VERSION 5.8 ;
BUSBITCHARS "[]" ;
DIVIDERCHAR "/" ;
UNITS
    DATABASE MICRONS 1000 ;
END UNITS

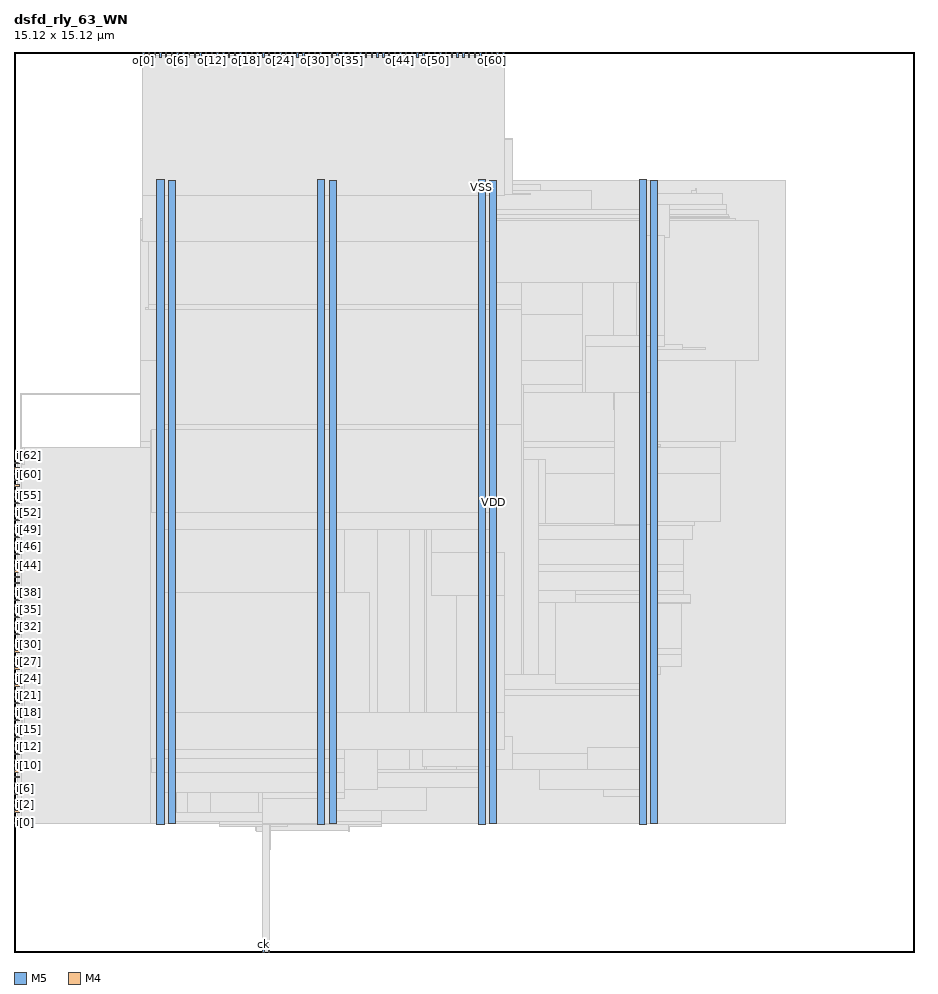
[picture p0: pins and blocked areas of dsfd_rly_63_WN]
MACRO dsfd_rly_63_WN
  FOREIGN dsfd_rly_63_WN 0 0 ;
  CLASS BLOCK ;
  SIZE 15.12 BY 15.12 ;
  PIN ck
    DIRECTION INPUT ;
    USE SIGNAL ;
    PORT
      LAYER M5 ;
        RECT  4.176 0 4.2 0.084 ;
    END
  END ck
  PIN i[0]
    DIRECTION INPUT ;
    USE SIGNAL ;
    PORT
      LAYER M4 ;
        RECT  0 2.16 0.084 2.184 ;
    END
  END i[0]
  PIN i[10]
    DIRECTION INPUT ;
    USE SIGNAL ;
    PORT
      LAYER M4 ;
        RECT  0 3.12 0.084 3.144 ;
    END
  END i[10]
  PIN i[11]
    DIRECTION INPUT ;
    USE SIGNAL ;
    PORT
      LAYER M4 ;
        RECT  0 3.216 0.084 3.24 ;
    END
  END i[11]
  PIN i[12]
    DIRECTION INPUT ;
    USE SIGNAL ;
    PORT
      LAYER M4 ;
        RECT  0 3.312 0.084 3.336 ;
    END
  END i[12]
  PIN i[13]
    DIRECTION INPUT ;
    USE SIGNAL ;
    PORT
      LAYER M4 ;
        RECT  0 3.408 0.084 3.432 ;
    END
  END i[13]
  PIN i[14]
    DIRECTION INPUT ;
    USE SIGNAL ;
    PORT
      LAYER M4 ;
        RECT  0 3.504 0.084 3.528 ;
    END
  END i[14]
  PIN i[15]
    DIRECTION INPUT ;
    USE SIGNAL ;
    PORT
      LAYER M4 ;
        RECT  0 3.6 0.084 3.624 ;
    END
  END i[15]
  PIN i[16]
    DIRECTION INPUT ;
    USE SIGNAL ;
    PORT
      LAYER M4 ;
        RECT  0 3.696 0.084 3.72 ;
    END
  END i[16]
  PIN i[17]
    DIRECTION INPUT ;
    USE SIGNAL ;
    PORT
      LAYER M4 ;
        RECT  0 3.792 0.084 3.816 ;
    END
  END i[17]
  PIN i[18]
    DIRECTION INPUT ;
    USE SIGNAL ;
    PORT
      LAYER M4 ;
        RECT  0 3.888 0.084 3.912 ;
    END
  END i[18]
  PIN i[19]
    DIRECTION INPUT ;
    USE SIGNAL ;
    PORT
      LAYER M4 ;
        RECT  0 3.984 0.084 4.008 ;
    END
  END i[19]
  PIN i[1]
    DIRECTION INPUT ;
    USE SIGNAL ;
    PORT
      LAYER M4 ;
        RECT  0 2.256 0.084 2.28 ;
    END
  END i[1]
  PIN i[20]
    DIRECTION INPUT ;
    USE SIGNAL ;
    PORT
      LAYER M4 ;
        RECT  0 4.08 0.084 4.104 ;
    END
  END i[20]
  PIN i[21]
    DIRECTION INPUT ;
    USE SIGNAL ;
    PORT
      LAYER M4 ;
        RECT  0 4.176 0.084 4.2 ;
    END
  END i[21]
  PIN i[22]
    DIRECTION INPUT ;
    USE SIGNAL ;
    PORT
      LAYER M4 ;
        RECT  0 4.272 0.084 4.296 ;
    END
  END i[22]
  PIN i[23]
    DIRECTION INPUT ;
    USE SIGNAL ;
    PORT
      LAYER M4 ;
        RECT  0 4.368 0.084 4.392 ;
    END
  END i[23]
  PIN i[24]
    DIRECTION INPUT ;
    USE SIGNAL ;
    PORT
      LAYER M4 ;
        RECT  0 4.464 0.084 4.488 ;
    END
  END i[24]
  PIN i[25]
    DIRECTION INPUT ;
    USE SIGNAL ;
    PORT
      LAYER M4 ;
        RECT  0 4.56 0.084 4.584 ;
    END
  END i[25]
  PIN i[26]
    DIRECTION INPUT ;
    USE SIGNAL ;
    PORT
      LAYER M4 ;
        RECT  0 4.656 0.084 4.68 ;
    END
  END i[26]
  PIN i[27]
    DIRECTION INPUT ;
    USE SIGNAL ;
    PORT
      LAYER M4 ;
        RECT  0 4.752 0.084 4.776 ;
    END
  END i[27]
  PIN i[28]
    DIRECTION INPUT ;
    USE SIGNAL ;
    PORT
      LAYER M4 ;
        RECT  0 4.848 0.084 4.872 ;
    END
  END i[28]
  PIN i[29]
    DIRECTION INPUT ;
    USE SIGNAL ;
    PORT
      LAYER M4 ;
        RECT  0 4.944 0.084 4.968 ;
    END
  END i[29]
  PIN i[2]
    DIRECTION INPUT ;
    USE SIGNAL ;
    PORT
      LAYER M4 ;
        RECT  0 2.352 0.084 2.376 ;
    END
  END i[2]
  PIN i[30]
    DIRECTION INPUT ;
    USE SIGNAL ;
    PORT
      LAYER M4 ;
        RECT  0 5.04 0.084 5.064 ;
    END
  END i[30]
  PIN i[31]
    DIRECTION INPUT ;
    USE SIGNAL ;
    PORT
      LAYER M4 ;
        RECT  0 5.136 0.084 5.16 ;
    END
  END i[31]
  PIN i[32]
    DIRECTION INPUT ;
    USE SIGNAL ;
    PORT
      LAYER M4 ;
        RECT  0 5.328 0.084 5.352 ;
    END
  END i[32]
  PIN i[33]
    DIRECTION INPUT ;
    USE SIGNAL ;
    PORT
      LAYER M4 ;
        RECT  0 5.424 0.084 5.448 ;
    END
  END i[33]
  PIN i[34]
    DIRECTION INPUT ;
    USE SIGNAL ;
    PORT
      LAYER M4 ;
        RECT  0 5.52 0.084 5.544 ;
    END
  END i[34]
  PIN i[35]
    DIRECTION INPUT ;
    USE SIGNAL ;
    PORT
      LAYER M4 ;
        RECT  0 5.616 0.084 5.64 ;
    END
  END i[35]
  PIN i[36]
    DIRECTION INPUT ;
    USE SIGNAL ;
    PORT
      LAYER M4 ;
        RECT  0 5.712 0.084 5.736 ;
    END
  END i[36]
  PIN i[37]
    DIRECTION INPUT ;
    USE SIGNAL ;
    PORT
      LAYER M4 ;
        RECT  0 5.808 0.084 5.832 ;
    END
  END i[37]
  PIN i[38]
    DIRECTION INPUT ;
    USE SIGNAL ;
    PORT
      LAYER M4 ;
        RECT  0 5.904 0.084 5.928 ;
    END
  END i[38]
  PIN i[39]
    DIRECTION INPUT ;
    USE SIGNAL ;
    PORT
      LAYER M4 ;
        RECT  0 6 0.084 6.024 ;
    END
  END i[39]
  PIN i[3]
    DIRECTION INPUT ;
    USE SIGNAL ;
    PORT
      LAYER M4 ;
        RECT  0 2.448 0.084 2.472 ;
    END
  END i[3]
  PIN i[40]
    DIRECTION INPUT ;
    USE SIGNAL ;
    PORT
      LAYER M4 ;
        RECT  0 6.096 0.084 6.12 ;
    END
  END i[40]
  PIN i[41]
    DIRECTION INPUT ;
    USE SIGNAL ;
    PORT
      LAYER M4 ;
        RECT  0 6.192 0.084 6.216 ;
    END
  END i[41]
  PIN i[42]
    DIRECTION INPUT ;
    USE SIGNAL ;
    PORT
      LAYER M4 ;
        RECT  0 6.288 0.084 6.312 ;
    END
  END i[42]
  PIN i[43]
    DIRECTION INPUT ;
    USE SIGNAL ;
    PORT
      LAYER M4 ;
        RECT  0 6.384 0.084 6.408 ;
    END
  END i[43]
  PIN i[44]
    DIRECTION INPUT ;
    USE SIGNAL ;
    PORT
      LAYER M4 ;
        RECT  0 6.48 0.084 6.504 ;
    END
  END i[44]
  PIN i[45]
    DIRECTION INPUT ;
    USE SIGNAL ;
    PORT
      LAYER M4 ;
        RECT  0 6.576 0.084 6.6 ;
    END
  END i[45]
  PIN i[46]
    DIRECTION INPUT ;
    USE SIGNAL ;
    PORT
      LAYER M4 ;
        RECT  0 6.672 0.084 6.696 ;
    END
  END i[46]
  PIN i[47]
    DIRECTION INPUT ;
    USE SIGNAL ;
    PORT
      LAYER M4 ;
        RECT  0 6.768 0.084 6.792 ;
    END
  END i[47]
  PIN i[48]
    DIRECTION INPUT ;
    USE SIGNAL ;
    PORT
      LAYER M4 ;
        RECT  0 6.864 0.084 6.888 ;
    END
  END i[48]
  PIN i[49]
    DIRECTION INPUT ;
    USE SIGNAL ;
    PORT
      LAYER M4 ;
        RECT  0 6.96 0.084 6.984 ;
    END
  END i[49]
  PIN i[4]
    DIRECTION INPUT ;
    USE SIGNAL ;
    PORT
      LAYER M4 ;
        RECT  0 2.544 0.084 2.568 ;
    END
  END i[4]
  PIN i[50]
    DIRECTION INPUT ;
    USE SIGNAL ;
    PORT
      LAYER M4 ;
        RECT  0 7.056 0.084 7.08 ;
    END
  END i[50]
  PIN i[51]
    DIRECTION INPUT ;
    USE SIGNAL ;
    PORT
      LAYER M4 ;
        RECT  0 7.152 0.084 7.176 ;
    END
  END i[51]
  PIN i[52]
    DIRECTION INPUT ;
    USE SIGNAL ;
    PORT
      LAYER M4 ;
        RECT  0 7.248 0.084 7.272 ;
    END
  END i[52]
  PIN i[53]
    DIRECTION INPUT ;
    USE SIGNAL ;
    PORT
      LAYER M4 ;
        RECT  0 7.344 0.084 7.368 ;
    END
  END i[53]
  PIN i[54]
    DIRECTION INPUT ;
    USE SIGNAL ;
    PORT
      LAYER M4 ;
        RECT  0 7.44 0.084 7.464 ;
    END
  END i[54]
  PIN i[55]
    DIRECTION INPUT ;
    USE SIGNAL ;
    PORT
      LAYER M4 ;
        RECT  0 7.536 0.084 7.56 ;
    END
  END i[55]
  PIN i[56]
    DIRECTION INPUT ;
    USE SIGNAL ;
    PORT
      LAYER M4 ;
        RECT  0 7.632 0.084 7.656 ;
    END
  END i[56]
  PIN i[57]
    DIRECTION INPUT ;
    USE SIGNAL ;
    PORT
      LAYER M4 ;
        RECT  0 7.728 0.084 7.752 ;
    END
  END i[57]
  PIN i[58]
    DIRECTION INPUT ;
    USE SIGNAL ;
    PORT
      LAYER M4 ;
        RECT  0 7.824 0.084 7.848 ;
    END
  END i[58]
  PIN i[59]
    DIRECTION INPUT ;
    USE SIGNAL ;
    PORT
      LAYER M4 ;
        RECT  0 7.92 0.084 7.944 ;
    END
  END i[59]
  PIN i[5]
    DIRECTION INPUT ;
    USE SIGNAL ;
    PORT
      LAYER M4 ;
        RECT  0 2.64 0.084 2.664 ;
    END
  END i[5]
  PIN i[60]
    DIRECTION INPUT ;
    USE SIGNAL ;
    PORT
      LAYER M4 ;
        RECT  0 8.016 0.084 8.04 ;
    END
  END i[60]
  PIN i[61]
    DIRECTION INPUT ;
    USE SIGNAL ;
    PORT
      LAYER M4 ;
        RECT  0 8.112 0.084 8.136 ;
    END
  END i[61]
  PIN i[62]
    DIRECTION INPUT ;
    USE SIGNAL ;
    PORT
      LAYER M4 ;
        RECT  0 8.208 0.084 8.232 ;
    END
  END i[62]
  PIN i[6]
    DIRECTION INPUT ;
    USE SIGNAL ;
    PORT
      LAYER M4 ;
        RECT  0 2.736 0.084 2.76 ;
    END
  END i[6]
  PIN i[7]
    DIRECTION INPUT ;
    USE SIGNAL ;
    PORT
      LAYER M4 ;
        RECT  0 2.832 0.084 2.856 ;
    END
  END i[7]
  PIN i[8]
    DIRECTION INPUT ;
    USE SIGNAL ;
    PORT
      LAYER M4 ;
        RECT  0 2.928 0.084 2.952 ;
    END
  END i[8]
  PIN i[9]
    DIRECTION INPUT ;
    USE SIGNAL ;
    PORT
      LAYER M4 ;
        RECT  0 3.024 0.084 3.048 ;
    END
  END i[9]
  PIN o[0]
    DIRECTION OUTPUT ;
    USE SIGNAL ;
    PORT
      LAYER M5 ;
        RECT  2.16 15.036 2.184 15.12 ;
    END
  END o[0]
  PIN o[10]
    DIRECTION OUTPUT ;
    USE SIGNAL ;
    PORT
      LAYER M5 ;
        RECT  3.12 15.036 3.144 15.12 ;
    END
  END o[10]
  PIN o[11]
    DIRECTION OUTPUT ;
    USE SIGNAL ;
    PORT
      LAYER M5 ;
        RECT  3.216 15.036 3.24 15.12 ;
    END
  END o[11]
  PIN o[12]
    DIRECTION OUTPUT ;
    USE SIGNAL ;
    PORT
      LAYER M5 ;
        RECT  3.312 15.036 3.336 15.12 ;
    END
  END o[12]
  PIN o[13]
    DIRECTION OUTPUT ;
    USE SIGNAL ;
    PORT
      LAYER M5 ;
        RECT  3.408 15.036 3.432 15.12 ;
    END
  END o[13]
  PIN o[14]
    DIRECTION OUTPUT ;
    USE SIGNAL ;
    PORT
      LAYER M5 ;
        RECT  3.504 15.036 3.528 15.12 ;
    END
  END o[14]
  PIN o[15]
    DIRECTION OUTPUT ;
    USE SIGNAL ;
    PORT
      LAYER M5 ;
        RECT  3.6 15.036 3.624 15.12 ;
    END
  END o[15]
  PIN o[16]
    DIRECTION OUTPUT ;
    USE SIGNAL ;
    PORT
      LAYER M5 ;
        RECT  3.696 15.036 3.72 15.12 ;
    END
  END o[16]
  PIN o[17]
    DIRECTION OUTPUT ;
    USE SIGNAL ;
    PORT
      LAYER M5 ;
        RECT  3.792 15.036 3.816 15.12 ;
    END
  END o[17]
  PIN o[18]
    DIRECTION OUTPUT ;
    USE SIGNAL ;
    PORT
      LAYER M5 ;
        RECT  3.888 15.036 3.912 15.12 ;
    END
  END o[18]
  PIN o[19]
    DIRECTION OUTPUT ;
    USE SIGNAL ;
    PORT
      LAYER M5 ;
        RECT  3.984 15.036 4.008 15.12 ;
    END
  END o[19]
  PIN o[1]
    DIRECTION OUTPUT ;
    USE SIGNAL ;
    PORT
      LAYER M5 ;
        RECT  2.256 15.036 2.28 15.12 ;
    END
  END o[1]
  PIN o[20]
    DIRECTION OUTPUT ;
    USE SIGNAL ;
    PORT
      LAYER M5 ;
        RECT  4.08 15.036 4.104 15.12 ;
    END
  END o[20]
  PIN o[21]
    DIRECTION OUTPUT ;
    USE SIGNAL ;
    PORT
      LAYER M5 ;
        RECT  4.176 15.036 4.2 15.12 ;
    END
  END o[21]
  PIN o[22]
    DIRECTION OUTPUT ;
    USE SIGNAL ;
    PORT
      LAYER M5 ;
        RECT  4.272 15.036 4.296 15.12 ;
    END
  END o[22]
  PIN o[23]
    DIRECTION OUTPUT ;
    USE SIGNAL ;
    PORT
      LAYER M5 ;
        RECT  4.368 15.036 4.392 15.12 ;
    END
  END o[23]
  PIN o[24]
    DIRECTION OUTPUT ;
    USE SIGNAL ;
    PORT
      LAYER M5 ;
        RECT  4.464 15.036 4.488 15.12 ;
    END
  END o[24]
  PIN o[25]
    DIRECTION OUTPUT ;
    USE SIGNAL ;
    PORT
      LAYER M5 ;
        RECT  4.56 15.036 4.584 15.12 ;
    END
  END o[25]
  PIN o[26]
    DIRECTION OUTPUT ;
    USE SIGNAL ;
    PORT
      LAYER M5 ;
        RECT  4.656 15.036 4.68 15.12 ;
    END
  END o[26]
  PIN o[27]
    DIRECTION OUTPUT ;
    USE SIGNAL ;
    PORT
      LAYER M5 ;
        RECT  4.752 15.036 4.776 15.12 ;
    END
  END o[27]
  PIN o[28]
    DIRECTION OUTPUT ;
    USE SIGNAL ;
    PORT
      LAYER M5 ;
        RECT  4.848 15.036 4.872 15.12 ;
    END
  END o[28]
  PIN o[29]
    DIRECTION OUTPUT ;
    USE SIGNAL ;
    PORT
      LAYER M5 ;
        RECT  4.944 15.036 4.968 15.12 ;
    END
  END o[29]
  PIN o[2]
    DIRECTION OUTPUT ;
    USE SIGNAL ;
    PORT
      LAYER M5 ;
        RECT  2.352 15.036 2.376 15.12 ;
    END
  END o[2]
  PIN o[30]
    DIRECTION OUTPUT ;
    USE SIGNAL ;
    PORT
      LAYER M5 ;
        RECT  5.04 15.036 5.064 15.12 ;
    END
  END o[30]
  PIN o[31]
    DIRECTION OUTPUT ;
    USE SIGNAL ;
    PORT
      LAYER M5 ;
        RECT  5.136 15.036 5.16 15.12 ;
    END
  END o[31]
  PIN o[32]
    DIRECTION OUTPUT ;
    USE SIGNAL ;
    PORT
      LAYER M5 ;
        RECT  5.328 15.036 5.352 15.12 ;
    END
  END o[32]
  PIN o[33]
    DIRECTION OUTPUT ;
    USE SIGNAL ;
    PORT
      LAYER M5 ;
        RECT  5.424 15.036 5.448 15.12 ;
    END
  END o[33]
  PIN o[34]
    DIRECTION OUTPUT ;
    USE SIGNAL ;
    PORT
      LAYER M5 ;
        RECT  5.52 15.036 5.544 15.12 ;
    END
  END o[34]
  PIN o[35]
    DIRECTION OUTPUT ;
    USE SIGNAL ;
    PORT
      LAYER M5 ;
        RECT  5.616 15.036 5.64 15.12 ;
    END
  END o[35]
  PIN o[36]
    DIRECTION OUTPUT ;
    USE SIGNAL ;
    PORT
      LAYER M5 ;
        RECT  5.712 15.036 5.736 15.12 ;
    END
  END o[36]
  PIN o[37]
    DIRECTION OUTPUT ;
    USE SIGNAL ;
    PORT
      LAYER M5 ;
        RECT  5.808 15.036 5.832 15.12 ;
    END
  END o[37]
  PIN o[38]
    DIRECTION OUTPUT ;
    USE SIGNAL ;
    PORT
      LAYER M5 ;
        RECT  5.904 15.036 5.928 15.12 ;
    END
  END o[38]
  PIN o[39]
    DIRECTION OUTPUT ;
    USE SIGNAL ;
    PORT
      LAYER M5 ;
        RECT  6 15.036 6.024 15.12 ;
    END
  END o[39]
  PIN o[3]
    DIRECTION OUTPUT ;
    USE SIGNAL ;
    PORT
      LAYER M5 ;
        RECT  2.448 15.036 2.472 15.12 ;
    END
  END o[3]
  PIN o[40]
    DIRECTION OUTPUT ;
    USE SIGNAL ;
    PORT
      LAYER M5 ;
        RECT  6.096 15.036 6.12 15.12 ;
    END
  END o[40]
  PIN o[41]
    DIRECTION OUTPUT ;
    USE SIGNAL ;
    PORT
      LAYER M5 ;
        RECT  6.192 15.036 6.216 15.12 ;
    END
  END o[41]
  PIN o[42]
    DIRECTION OUTPUT ;
    USE SIGNAL ;
    PORT
      LAYER M5 ;
        RECT  6.288 15.036 6.312 15.12 ;
    END
  END o[42]
  PIN o[43]
    DIRECTION OUTPUT ;
    USE SIGNAL ;
    PORT
      LAYER M5 ;
        RECT  6.384 15.036 6.408 15.12 ;
    END
  END o[43]
  PIN o[44]
    DIRECTION OUTPUT ;
    USE SIGNAL ;
    PORT
      LAYER M5 ;
        RECT  6.48 15.036 6.504 15.12 ;
    END
  END o[44]
  PIN o[45]
    DIRECTION OUTPUT ;
    USE SIGNAL ;
    PORT
      LAYER M5 ;
        RECT  6.576 15.036 6.6 15.12 ;
    END
  END o[45]
  PIN o[46]
    DIRECTION OUTPUT ;
    USE SIGNAL ;
    PORT
      LAYER M5 ;
        RECT  6.672 15.036 6.696 15.12 ;
    END
  END o[46]
  PIN o[47]
    DIRECTION OUTPUT ;
    USE SIGNAL ;
    PORT
      LAYER M5 ;
        RECT  6.768 15.036 6.792 15.12 ;
    END
  END o[47]
  PIN o[48]
    DIRECTION OUTPUT ;
    USE SIGNAL ;
    PORT
      LAYER M5 ;
        RECT  6.864 15.036 6.888 15.12 ;
    END
  END o[48]
  PIN o[49]
    DIRECTION OUTPUT ;
    USE SIGNAL ;
    PORT
      LAYER M5 ;
        RECT  6.96 15.036 6.984 15.12 ;
    END
  END o[49]
  PIN o[4]
    DIRECTION OUTPUT ;
    USE SIGNAL ;
    PORT
      LAYER M5 ;
        RECT  2.544 15.036 2.568 15.12 ;
    END
  END o[4]
  PIN o[50]
    DIRECTION OUTPUT ;
    USE SIGNAL ;
    PORT
      LAYER M5 ;
        RECT  7.056 15.036 7.08 15.12 ;
    END
  END o[50]
  PIN o[51]
    DIRECTION OUTPUT ;
    USE SIGNAL ;
    PORT
      LAYER M5 ;
        RECT  7.152 15.036 7.176 15.12 ;
    END
  END o[51]
  PIN o[52]
    DIRECTION OUTPUT ;
    USE SIGNAL ;
    PORT
      LAYER M5 ;
        RECT  7.248 15.036 7.272 15.12 ;
    END
  END o[52]
  PIN o[53]
    DIRECTION OUTPUT ;
    USE SIGNAL ;
    PORT
      LAYER M5 ;
        RECT  7.344 15.036 7.368 15.12 ;
    END
  END o[53]
  PIN o[54]
    DIRECTION OUTPUT ;
    USE SIGNAL ;
    PORT
      LAYER M5 ;
        RECT  7.44 15.036 7.464 15.12 ;
    END
  END o[54]
  PIN o[55]
    DIRECTION OUTPUT ;
    USE SIGNAL ;
    PORT
      LAYER M5 ;
        RECT  7.536 15.036 7.56 15.12 ;
    END
  END o[55]
  PIN o[56]
    DIRECTION OUTPUT ;
    USE SIGNAL ;
    PORT
      LAYER M5 ;
        RECT  7.632 15.036 7.656 15.12 ;
    END
  END o[56]
  PIN o[57]
    DIRECTION OUTPUT ;
    USE SIGNAL ;
    PORT
      LAYER M5 ;
        RECT  7.728 15.036 7.752 15.12 ;
    END
  END o[57]
  PIN o[58]
    DIRECTION OUTPUT ;
    USE SIGNAL ;
    PORT
      LAYER M5 ;
        RECT  7.824 15.036 7.848 15.12 ;
    END
  END o[58]
  PIN o[59]
    DIRECTION OUTPUT ;
    USE SIGNAL ;
    PORT
      LAYER M5 ;
        RECT  7.92 15.036 7.944 15.12 ;
    END
  END o[59]
  PIN o[5]
    DIRECTION OUTPUT ;
    USE SIGNAL ;
    PORT
      LAYER M5 ;
        RECT  2.64 15.036 2.664 15.12 ;
    END
  END o[5]
  PIN o[60]
    DIRECTION OUTPUT ;
    USE SIGNAL ;
    PORT
      LAYER M5 ;
        RECT  8.016 15.036 8.04 15.12 ;
    END
  END o[60]
  PIN o[61]
    DIRECTION OUTPUT ;
    USE SIGNAL ;
    PORT
      LAYER M5 ;
        RECT  8.112 15.036 8.136 15.12 ;
    END
  END o[61]
  PIN o[62]
    DIRECTION OUTPUT ;
    USE SIGNAL ;
    PORT
      LAYER M5 ;
        RECT  8.208 15.036 8.232 15.12 ;
    END
  END o[62]
  PIN o[6]
    DIRECTION OUTPUT ;
    USE SIGNAL ;
    PORT
      LAYER M5 ;
        RECT  2.736 15.036 2.76 15.12 ;
    END
  END o[6]
  PIN o[7]
    DIRECTION OUTPUT ;
    USE SIGNAL ;
    PORT
      LAYER M5 ;
        RECT  2.832 15.036 2.856 15.12 ;
    END
  END o[7]
  PIN o[8]
    DIRECTION OUTPUT ;
    USE SIGNAL ;
    PORT
      LAYER M5 ;
        RECT  2.928 15.036 2.952 15.12 ;
    END
  END o[8]
  PIN o[9]
    DIRECTION OUTPUT ;
    USE SIGNAL ;
    PORT
      LAYER M5 ;
        RECT  3.024 15.036 3.048 15.12 ;
    END
  END o[9]
  PIN rs
    DIRECTION INPUT ;
    USE SIGNAL ;
    PORT
      LAYER M5 ;
        RECT  4.272 0 4.296 0.084 ;
    END
  END rs
  PIN VDD
    DIRECTION INOUT ;
    USE POWER ;
    PORT
      LAYER M5 ;
        RECT  10.692 2.151 10.812 12.969 ;
        RECT  7.992 2.151 8.112 12.969 ;
        RECT  5.292 2.151 5.412 12.969 ;
        RECT  2.592 2.151 2.712 12.969 ;
    END
  END VDD
  PIN VSS
    DIRECTION INOUT ;
    USE GROUND ;
    PORT
      LAYER M5 ;
        RECT  10.5 2.137 10.62 12.983 ;
        RECT  7.8 2.137 7.92 12.983 ;
        RECT  5.1 2.137 5.22 12.983 ;
        RECT  2.4 2.137 2.52 12.983 ;
    END
  END VSS
  OBS
    LAYER RVTN ;
     RECT  2.16 2.16 12.96 2.295 ;
     RECT  2.16 2.565 12.96 2.835 ;
     RECT  2.16 3.105 12.96 3.375 ;
     RECT  2.16 3.645 12.96 3.915 ;
     RECT  2.16 4.185 12.96 4.455 ;
     RECT  2.16 4.725 12.96 4.995 ;
     RECT  2.16 5.265 12.96 5.535 ;
     RECT  2.16 5.805 12.96 6.075 ;
     RECT  2.16 6.345 12.96 6.615 ;
     RECT  2.16 6.885 12.96 7.155 ;
     RECT  2.16 7.425 12.96 7.695 ;
     RECT  2.16 7.965 12.96 8.235 ;
     RECT  2.16 8.505 12.96 8.775 ;
     RECT  2.16 9.045 12.96 9.315 ;
     RECT  2.16 9.585 12.96 9.855 ;
     RECT  2.16 10.125 12.96 10.395 ;
     RECT  2.16 10.665 12.96 10.935 ;
     RECT  2.16 11.205 12.96 11.475 ;
     RECT  2.16 11.745 12.96 12.015 ;
     RECT  2.16 12.285 12.96 12.555 ;
     RECT  2.16 12.825 12.96 12.96 ;
    LAYER RVTP ;
     RECT  2.16 2.295 12.96 2.565 ;
     RECT  2.16 2.835 12.96 3.105 ;
     RECT  2.16 3.375 12.96 3.645 ;
     RECT  2.16 3.915 12.96 4.185 ;
     RECT  2.16 4.455 12.96 4.725 ;
     RECT  2.16 4.995 12.96 5.265 ;
     RECT  2.16 5.535 12.96 5.805 ;
     RECT  2.16 6.075 12.96 6.345 ;
     RECT  2.16 6.615 12.96 6.885 ;
     RECT  2.16 7.155 12.96 7.425 ;
     RECT  2.16 7.695 12.96 7.965 ;
     RECT  2.16 8.235 12.96 8.505 ;
     RECT  2.16 8.775 12.96 9.045 ;
     RECT  2.16 9.315 12.96 9.585 ;
     RECT  2.16 9.855 12.96 10.125 ;
     RECT  2.16 10.395 12.96 10.665 ;
     RECT  2.16 10.935 12.96 11.205 ;
     RECT  2.16 11.475 12.96 11.745 ;
     RECT  2.16 12.015 12.96 12.285 ;
     RECT  2.16 12.555 12.96 12.825 ;
    LAYER M1 ;
     RECT  2.16 2.151 12.96 12.969 ;
    LAYER M2 ;
     RECT  0.103 3.69 0.175 3.708 ;
     RECT  0.175 3.618 0.499 3.708 ;
     RECT  2.119 8.478 2.155 8.496 ;
     RECT  2.119 12.294 2.155 12.312 ;
     RECT  0.499 3.114 2.16 3.708 ;
     RECT  0.103 4.464 2.16 4.482 ;
     RECT  0.535 5.58 2.16 5.598 ;
     RECT  0.535 6.696 2.16 6.714 ;
     RECT  2.155 8.046 2.16 8.496 ;
     RECT  0.103 9.36 2.16 9.378 ;
     RECT  2.155 12.294 2.16 12.384 ;
     RECT  2.16 2.151 3.451 12.969 ;
     RECT  3.451 2.106 4.063 12.969 ;
     RECT  4.063 2.034 5.639 12.969 ;
     RECT  5.639 2.106 6.179 12.969 ;
     RECT  6.179 2.151 12.96 12.969 ;
    LAYER M3 ;
     RECT  4.284 1.723 4.302 2.029 ;
     RECT  4.068 2.029 4.302 2.101 ;
     RECT  5.616 2.029 5.634 2.101 ;
     RECT  3.456 2.101 4.59 2.143 ;
     RECT  5.616 2.101 6.174 2.143 ;
     RECT  2.415 2.143 2.505 2.155 ;
     RECT  2.304 2.155 2.505 2.191 ;
     RECT  3.456 2.143 6.174 2.191 ;
     RECT  2.304 2.191 6.174 2.371 ;
     RECT  7.815 2.143 7.905 2.413 ;
     RECT  10.515 2.143 10.605 2.413 ;
     RECT  10.515 2.413 10.797 2.605 ;
     RECT  9.9 2.605 10.797 2.731 ;
     RECT  2.304 2.371 6.93 2.767 ;
     RECT  7.815 2.413 8.097 2.767 ;
     RECT  2.304 2.767 8.097 3.019 ;
     RECT  2.196 3.019 8.097 3.109 ;
     RECT  8.82 2.731 10.797 3.109 ;
     RECT  2.196 3.109 10.797 3.173 ;
     RECT  0.504 3.109 0.522 3.379 ;
     RECT  0.504 3.379 0.558 3.533 ;
     RECT  0.504 3.533 0.522 3.613 ;
     RECT  0.18 3.613 0.522 3.685 ;
     RECT  2.304 3.173 10.797 4.315 ;
     RECT  2.268 4.315 10.797 4.415 ;
     RECT  0.108 3.685 0.522 4.589 ;
     RECT  2.304 4.415 10.797 4.657 ;
     RECT  0.108 4.589 0.198 4.685 ;
     RECT  2.304 4.657 10.854 4.801 ;
     RECT  2.304 4.801 11.214 4.991 ;
     RECT  9.288 4.991 11.214 5.099 ;
     RECT  2.304 4.991 8.55 5.323 ;
     RECT  2.268 5.323 8.55 5.563 ;
     RECT  0.144 4.685 0.198 5.575 ;
     RECT  2.196 5.563 8.55 5.603 ;
     RECT  0.144 5.575 0.558 5.851 ;
     RECT  9.432 5.099 11.214 5.851 ;
     RECT  9.432 5.851 11.358 5.999 ;
     RECT  0.144 5.851 1.17 6.077 ;
     RECT  2.304 5.603 8.55 6.079 ;
     RECT  9.432 5.999 11.25 6.079 ;
     RECT  0.18 6.077 1.17 6.221 ;
     RECT  2.304 6.079 11.25 6.385 ;
     RECT  2.268 6.385 11.25 6.509 ;
     RECT  2.304 6.509 11.25 6.925 ;
     RECT  0.18 6.221 0.558 6.955 ;
     RECT  0.18 6.955 1.17 7.085 ;
     RECT  2.304 6.925 11.394 7.159 ;
     RECT  0.18 7.085 0.198 7.195 ;
     RECT  2.304 7.159 11.43 7.231 ;
     RECT  1.152 7.085 1.17 7.373 ;
     RECT  0.144 7.195 0.198 7.819 ;
     RECT  2.304 7.231 11.862 8.041 ;
     RECT  0.108 7.819 0.198 8.107 ;
     RECT  0.108 8.107 0.342 8.237 ;
     RECT  2.16 8.041 11.862 8.473 ;
     RECT  2.124 8.473 11.862 8.581 ;
     RECT  0.108 8.237 0.126 9.383 ;
     RECT  2.124 8.581 12.114 9.931 ;
     RECT  2.124 9.931 12.51 12.281 ;
     RECT  2.124 12.281 12.114 12.317 ;
     RECT  2.16 12.317 12.006 12.389 ;
     RECT  2.376 12.389 11.97 12.479 ;
     RECT  10.515 12.479 11.97 12.551 ;
     RECT  10.515 12.551 11.898 12.749 ;
     RECT  2.376 12.479 9.702 12.785 ;
     RECT  10.515 12.749 10.638 12.785 ;
     RECT  11.376 12.749 11.466 12.785 ;
     RECT  11.448 12.785 11.466 12.821 ;
     RECT  2.376 12.785 8.838 12.893 ;
     RECT  10.515 12.785 10.605 12.977 ;
     RECT  2.376 12.893 8.37 13.661 ;
     RECT  2.376 13.661 4.194 14.237 ;
     RECT  5.4 13.661 7.362 14.237 ;
     RECT  4.176 14.237 4.194 14.285 ;
     RECT  2.556 14.237 3.294 14.957 ;
     RECT  2.628 14.957 3.294 15.005 ;
     RECT  5.58 14.237 5.598 15.005 ;
     RECT  7.344 14.237 7.362 15.005 ;
    LAYER M4 ;
     RECT  0.06 2.16 0.133 8.232 ;
     RECT  0.133 2.16 2.293 8.472 ;
     RECT  2.341 14.976 2.365 15 ;
     RECT  2.293 2.16 2.408 8.76 ;
     RECT  2.213 10.8 2.408 10.824 ;
     RECT  2.149 11.952 2.408 11.976 ;
     RECT  2.408 2.148 2.512 12.972 ;
     RECT  2.512 2.352 2.725 12.972 ;
     RECT  2.725 2.352 2.917 13.08 ;
     RECT  2.365 14.208 2.917 15 ;
     RECT  2.917 2.352 3.305 15 ;
     RECT  3.305 2.352 4.115 14.28 ;
     RECT  4.115 10.272 4.211 14.28 ;
     RECT  4.115 2.352 4.229 9.288 ;
     RECT  4.229 1.728 4.313 9.288 ;
     RECT  4.313 2.148 5.108 9.288 ;
     RECT  4.211 10.272 5.108 13.656 ;
     RECT  5.108 2.148 5.212 13.656 ;
     RECT  5.212 2.418 5.317 13.656 ;
     RECT  4.885 14.928 5.317 14.952 ;
     RECT  5.317 2.418 5.404 14.952 ;
     RECT  5.404 10.944 5.509 14.952 ;
     RECT  5.509 10.944 5.537 15 ;
     RECT  5.404 2.592 5.555 8.424 ;
     RECT  5.537 11.424 5.609 15 ;
     RECT  5.555 2.736 6.113 8.424 ;
     RECT  5.609 11.424 6.373 14.232 ;
     RECT  6.113 3.072 6.649 8.424 ;
     RECT  6.373 11.424 6.721 11.448 ;
     RECT  6.373 12.528 6.833 14.232 ;
     RECT  6.649 3.072 6.901 8.856 ;
     RECT  6.901 3.072 6.937 8.904 ;
     RECT  6.833 13.056 7.157 14.232 ;
     RECT  6.721 10.8 7.333 11.448 ;
     RECT  7.237 14.976 7.373 15 ;
     RECT  6.937 3.072 7.441 9.096 ;
     RECT  7.333 10.464 7.441 11.448 ;
     RECT  7.441 3.072 7.808 11.448 ;
     RECT  7.157 13.056 7.808 13.656 ;
     RECT  7.808 2.148 7.912 13.656 ;
     RECT  7.912 2.418 8.104 13.656 ;
     RECT  8.104 3.072 8.381 3.624 ;
     RECT  8.104 12.72 8.381 13.656 ;
     RECT  8.104 4.656 8.531 11.256 ;
     RECT  8.531 4.656 8.561 9.528 ;
     RECT  8.381 12.72 8.669 12.744 ;
     RECT  8.561 4.656 8.813 8.28 ;
     RECT  8.813 7.2 8.921 8.28 ;
     RECT  8.813 4.656 9.097 5.88 ;
     RECT  8.561 9.408 9.548 9.528 ;
     RECT  8.531 10.704 9.548 11.256 ;
     RECT  8.381 3.072 9.637 3.336 ;
     RECT  9.548 9.408 10.069 11.256 ;
     RECT  8.921 7.2 10.465 8.04 ;
     RECT  10.069 9.12 10.465 11.256 ;
     RECT  9.637 3.072 10.508 3.432 ;
     RECT  9.097 4.512 10.508 5.88 ;
     RECT  10.465 7.2 10.508 11.256 ;
     RECT  10.508 2.148 10.612 12.972 ;
     RECT  10.612 2.418 10.804 12.702 ;
     RECT  10.804 8.496 10.865 8.52 ;
     RECT  10.804 12 11.009 12.552 ;
     RECT  10.804 10.128 11.225 10.2 ;
     RECT  10.804 5.856 11.369 5.88 ;
     RECT  11.225 10.128 11.621 10.152 ;
     RECT  11.009 12.336 12.017 12.36 ;
    LAYER M5 ;
     RECT  4.176 0.016 4.296 2.137 ;
     RECT  2.4 2.137 2.52 2.151 ;
     RECT  4.176 2.137 5.22 2.151 ;
     RECT  7.8 2.137 7.92 2.151 ;
     RECT  10.5 2.137 10.62 2.151 ;
     RECT  4.176 2.151 5.412 2.581 ;
     RECT  2.4 2.151 2.712 2.677 ;
     RECT  4.176 2.581 5.544 2.677 ;
     RECT  2.4 2.677 5.544 3.013 ;
     RECT  7.8 2.151 8.112 3.109 ;
     RECT  2.304 3.013 5.544 3.251 ;
     RECT  2.4 3.251 5.544 3.397 ;
     RECT  6.864 3.109 8.112 3.397 ;
     RECT  2.4 3.397 8.232 4.019 ;
     RECT  0.144 3.637 0.168 4.499 ;
     RECT  7.8 4.019 8.232 5.989 ;
     RECT  2.4 4.019 5.976 6.035 ;
     RECT  7.008 5.989 8.232 6.707 ;
     RECT  2.4 6.035 5.544 7.093 ;
     RECT  7.008 6.707 8.112 7.093 ;
     RECT  10.5 2.151 10.812 7.189 ;
     RECT  2.4 7.093 8.112 7.381 ;
     RECT  0.144 8.197 0.168 8.483 ;
     RECT  2.304 7.381 8.112 8.771 ;
     RECT  2.4 8.771 8.112 8.869 ;
     RECT  10.08 7.189 10.812 9.397 ;
     RECT  9.6 9.397 10.812 10.165 ;
     RECT  9.6 10.165 10.92 10.355 ;
     RECT  2.4 8.869 8.52 10.789 ;
     RECT  2.256 10.789 8.52 10.883 ;
     RECT  2.256 10.883 8.112 11.941 ;
     RECT  10.5 10.355 10.92 12.035 ;
     RECT  2.16 11.941 8.112 12.709 ;
     RECT  10.5 12.035 10.812 12.969 ;
     RECT  10.5 12.969 10.62 12.983 ;
     RECT  2.16 12.709 8.232 15.056 ;
  END
END dsfd_rly_63_WN
END LIBRARY
